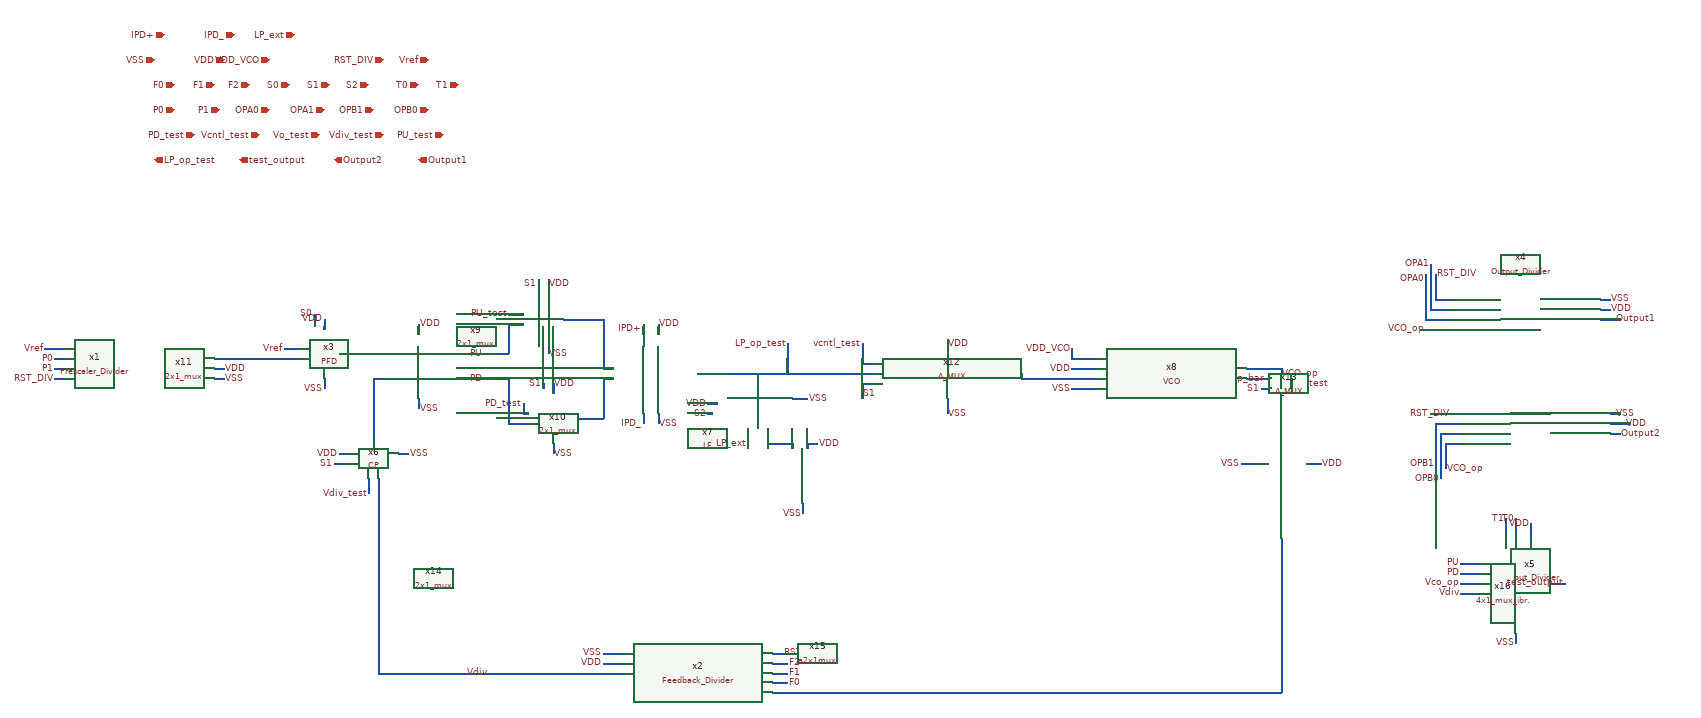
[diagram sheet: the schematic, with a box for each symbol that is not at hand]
v {xschem version=3.1.0 file_version=1.2
}
G {}
K {}
V {}
S {}
E {}
N 160 -760 180 -760 {
lab=P0}
N 160 -740 180 -740 {
lab=P1}
N 160 -720 180 -720 {
lab=RST_DIV}
N 480 -720 500 -720 {
lab=VSS}
N 480 -740 500 -740 {
lab=VDD}
N 890 -830 890 -810 {
lab=VDD}
N 890 -680 890 -660 {
lab=VSS}
N 800 -770 820 -770 {
lab=#net1}
N 800 -720 820 -720 {
lab=#net2}
N 960 -720 980 -720 {
lab=PD}
N 980 -770 1070 -770 {
lab=PU}
N 980 -720 1070 -720 {
lab=PD}
N 1010 -130 1300 -130 {
lab=Vdiv}
N 2200 -760 2240 -760 {
lab=VDD_VCO}
N 960 -770 980 -770 {
lab=PU}
N 2200 -780 2200 -760 {
lab=VDD_VCO}
N 1260 -170 1300 -170 {
lab=VSS}
N 1260 -150 1300 -150 {
lab=VDD}
N 1600 -150 1630 -150 {
lab=F2}
N 1600 -170 1630 -170 {
lab=RST_DIV}
N 2240 -760 2250 -760 {
lab=VDD_VCO}
N 1600 -110 1630 -110 {
lab=F0}
N 1600 -130 1630 -130 {
lab=F1}
N 2930 -880 2960 -880 {
lab=RST_DIV}
N 2930 -930 2930 -880 {
lab=RST_DIV}
N 2900 -820 2960 -820 {
lab=VCO_op}
N 2920 -860 2960 -860 {
lab=OPA1}
N 2920 -930 2920 -860 {
lab=OPA1}
N 2910 -840 2960 -840 {
lab=OPA0}
N 2910 -930 2910 -840 {
lab=OPA0}
N 3260 -880 3280 -880 {
lab=VSS}
N 3260 -860 3280 -860 {
lab=VDD}
N 3260 -840 3300 -840 {
lab=Output1}
N 2920 -950 2920 -930 {
lab=OPA1}
N 2950 -590 2980 -590 {
lab=VCO_op}
N 2950 -590 2950 -540 {
lab=VCO_op}
N 2920 -650 2980 -650 {
lab=RST_DIV}
N 2940 -610 2980 -610 {
lab=OPB0}
N 2940 -610 2940 -540 {
lab=OPB0}
N 2930 -630 2980 -630 {
lab=OPB1}
N 2930 -630 2930 -540 {
lab=OPB1}
N 3280 -650 3300 -650 {
lab=VSS}
N 3280 -610 3300 -610 {
lab=Output2}
N 3280 -630 3320 -630 {
lab=VDD}
N 2940 -540 2940 -520 {
lab=OPB0}
N 1370 -830 1370 -810 {
lab=VDD}
N 1370 -650 1370 -630 {
lab=VSS}
N 1260 -740 1280 -740 {
lab=#net3}
N 1260 -720 1280 -720 {
lab=#net4}
N 1340 -830 1340 -810 {
lab=IPD+}
N 1340 -650 1340 -630 {
lab=IPD_}
N 570 -760 600 -760 {
lab=#net5}
N 140 -780 170 -780 {
lab=Vref}
N 480 -760 550 -760 {
lab=#net5}
N 550 -760 570 -760 {
lab=#net5}
N 170 -780 180 -780 {
lab=Vref}
N 1070 -720 1070 -630 {
lab=PD}
N 1070 -630 1110 -630 {
lab=PD}
N 1100 -650 1110 -650 {
lab=PD_test}
N 1100 -670 1100 -650 {
lab=PD_test}
N 1070 -830 1070 -770 {
lab=PU}
N 1070 -830 1100 -830 {
lab=PU}
N 1150 -790 1150 -770 {
lab=VSS}
N 1140 -710 1140 -700 {
lab=S1}
N 1160 -710 1160 -690 {
lab=VDD}
N 1180 -840 1260 -840 {
lab=#net3}
N 1260 -840 1260 -770 {
lab=#net3}
N 1260 -720 1260 -640 {
lab=#net4}
N 1190 -640 1260 -640 {
lab=#net4}
N 1260 -770 1260 -740 {
lab=#net3}
N 1130 -920 1130 -900 {
lab=S1}
N 1150 -920 1150 -890 {
lab=VDD}
N 1070 -850 1100 -850 {
lab=PU_test}
N 1160 -590 1160 -570 {
lab=VSS}
N 700 -720 700 -700 {
lab=VSS}
N 700 -840 700 -820 {
lab=VDD}
N 680 -850 680 -830 {
lab=S0}
N 600 -760 650 -760 {
lab=#net5}
N 620 -780 650 -780 {
lab=Vref}
N 1950 -800 1950 -780 {
lab=VDD}
N 1950 -680 1950 -650 {
lab=VSS}
N 1780 -750 1800 -750 {
lab=vcntl_test}
N 1780 -790 1780 -750 {
lab=vcntl_test}
N 1780 -710 1800 -710 {
lab=S1}
N 1780 -710 1780 -680 {
lab=S1}
N 2640 -720 2640 -700 {
lab=Vo_test}
N 2620 -110 2620 -100 {
lab=#net6}
N 2540 -550 2570 -550 {
lab=VSS}
N 2670 -550 2700 -550 {
lab=VDD}
N 2580 -700 2600 -700 {
lab=S1}
N 2620 -100 2620 -90 {
lab=#net6}
N 2270 -90 2620 -90 {
lab=#net6}
N 1600 -90 2270 -90 {
lab=#net6}
N 2100 -720 2250 -720 {
lab=#net7}
N 2100 -730 2100 -720 {
lab=#net7}
N 2200 -740 2250 -740 {
lab=VDD}
N 2200 -700 2250 -700 {
lab=VSS}
N 2550 -740 2620 -740 {
lab=VCO_op}
N 2550 -720 2600 -720 {
lab=VCO_op_bar}
N 2620 -740 2620 -700 {
lab=VCO_op}
N 730 -770 790 -770 {
lab=#net1}
N 850 -570 870 -570 {
lab=VSS}
N 730 -570 750 -570 {
lab=VDD}
N 720 -550 740 -550 {
lab=S1}
N 810 -520 810 -470 {
lab=Vdiv}
N 790 -520 790 -490 {
lab=Vdiv_test}
N 800 -660 800 -600 {
lab=#net2}
N 810 -470 810 -420 {
lab=Vdiv}
N 800 -720 800 -660 {
lab=#net2}
N 790 -770 800 -770 {
lab=#net1}
N 1660 -470 1660 -450 {
lab=VSS}
N 1670 -590 1670 -580 {
lab=VDD}
N 1670 -590 1690 -590 {
lab=VDD}
N 1470 -670 1490 -670 {
lab=VDD}
N 1640 -680 1670 -680 {
lab=VSS}
N 1550 -620 1550 -590 {
lab=LP_ext}
N 1640 -590 1640 -580 {
lab=#net8}
N 1590 -590 1640 -590 {
lab=#net8}
N 1590 -620 1590 -590 {
lab=#net8}
N 1570 -730 1570 -720 {
lab=LP_op_test}
N 810 -130 1010 -130 {
lab=Vdiv}
N 810 -420 810 -300 {
lab=Vdiv}
N 2620 -230 2620 -110 {
lab=#net6}
N 810 -300 810 -130 {
lab=Vdiv}
N 2620 -400 2620 -240 {
lab=#net6}
N 2620 -240 2620 -230 {
lab=#net6}
N 1470 -650 1480 -650 {
lab=S2}
N 1450 -730 1800 -730 {
lab=LP_op_test}
N 2980 -350 3020 -350 {
lab=PU}
N 2980 -330 3020 -330 {
lab=PD}
N 2980 -310 3020 -310 {
lab=Vco_op}
N 2980 -290 3020 -290 {
lab=Vdiv}
N 1630 -790 1630 -730 {
lab=LP_op_test}
N 3120 -430 3120 -400 {
lab=VDD}
N 3090 -440 3090 -410 {
lab=T0}
N 3070 -440 3070 -410 {
lab=T1}
N 3090 -210 3090 -190 {
lab=VSS}
N 3160 -310 3190 -310 {
lab=test_output}
C {devices/ipin.sym} 710 -1310 0 0 {name=p45 lab=S1}
C {devices/ipin.sym} 630 -1310 0 0 {name=p46 lab=S0}
C {devices/ipin.sym} 890 -1310 0 0 {name=p47 lab=T0}
C {devices/ipin.sym} 970 -1310 0 0 {name=p48 lab=T1}
C {devices/iopin.sym} 500 -1360 0 0 {name=p58 lab=VDD}
C {devices/iopin.sym} 590 -1360 0 0 {name=p59 lab=VDD_VCO}
C {devices/ipin.sym} 910 -1360 0 0 {name=p60 lab=Vref}
C {devices/ipin.sym} 480 -1310 0 0 {name=p62 lab=F1}
C {devices/ipin.sym} 550 -1310 0 0 {name=p63 lab=F2}
C {devices/ipin.sym} 400 -1260 0 0 {name=p64 lab=P0}
C {devices/ipin.sym} 490 -1260 0 0 {name=p65 lab=P1}
C {devices/ipin.sym} 590 -1260 0 0 {name=p66 lab=OPA0}
C {devices/ipin.sym} 820 -1360 0 0 {name=p67 lab=RST_DIV}
C {devices/ipin.sym} 400 -1310 0 0 {name=p68 lab=F0}
C {devices/ipin.sym} 700 -1260 0 0 {name=p69 lab=OPA1}
C {devices/ipin.sym} 800 -1260 0 0 {name=p70 lab=OPB1}
C {devices/ipin.sym} 910 -1260 0 0 {name=p71 lab=OPB0}
C {devices/ipin.sym} 820 -1210 0 0 {name=p72 lab=Vdiv_test}
C {devices/ipin.sym} 940 -1210 0 0 {name=p73 lab=PU_test}
C {devices/ipin.sym} 440 -1210 0 0 {name=p74 lab=PD_test}
C {devices/ipin.sym} 570 -1210 0 0 {name=p75 lab=Vcntl_test}
C {devices/ipin.sym} 690 -1210 0 0 {name=p76 lab=Vo_test}
C {devices/opin.sym} 360 -1160 0 0 {name=p77 lab=LP_op_test}
C {devices/opin.sym} 530 -1160 0 0 {name=p78 lab=test_output}
C {devices/opin.sym} 720 -1160 0 0 {name=p79 lab=Output2}
C {devices/opin.sym} 890 -1160 0 0 {name=p80 lab=Output1}
C {devices/iopin.sym} 360 -1360 0 0 {name=p57 lab=VSS}
C {devices/lab_pin.sym} 160 -740 0 0 {name=p139 sig_type=std_logic lab=P1}
C {devices/lab_pin.sym} 160 -760 0 0 {name=p140 sig_type=std_logic lab=P0}
C {devices/lab_pin.sym} 140 -780 0 0 {name=p141 sig_type=std_logic lab=Vref
}
C {devices/lab_pin.sym} 500 -720 2 0 {name=p142 sig_type=std_logic lab=VSS}
C {devices/lab_pin.sym} 500 -740 2 0 {name=p143 sig_type=std_logic lab=VDD}
C {devices/lab_pin.sym} 160 -720 0 0 {name=p144 sig_type=std_logic lab=RST_DIV}
C {PFD.sym} 600 -560 0 0 {name=x3}
C {devices/lab_pin.sym} 890 -830 2 0 {name=p9 sig_type=std_logic lab=VDD}
C {devices/lab_wire.sym} 890 -660 2 0 {name=p10 sig_type=std_logic lab=VSS}
C {devices/lab_pin.sym} 1030 -130 1 0 {name=p28 sig_type=std_logic lab=Vdiv
}
C {devices/lab_pin.sym} 2200 -780 0 0 {name=p12 sig_type=std_logic lab=VDD_VCO}
C {devices/lab_pin.sym} 2590 -720 1 0 {name=p13 sig_type=std_logic lab=VCO_op_bar
}
C {devices/lab_pin.sym} 1260 -150 0 0 {name=p14 sig_type=std_logic lab=VDD}
C {devices/lab_wire.sym} 1260 -170 1 0 {name=p15 sig_type=std_logic lab=VSS}
C {devices/lab_pin.sym} 1630 -790 1 0 {name=p19 sig_type=std_logic lab=LP_op_test
}
C {devices/lab_pin.sym} 1020 -770 1 0 {name=p20 sig_type=std_logic lab=PU}
C {devices/lab_pin.sym} 1020 -720 1 0 {name=p21 sig_type=std_logic lab=PD}
C {Feedback_Divider.sym} 1450 -130 0 1 {name=x2}
C {devices/lab_pin.sym} 1630 -110 2 0 {name=p22 sig_type=std_logic lab=F0}
C {devices/lab_pin.sym} 1630 -130 2 0 {name=p23 sig_type=std_logic lab=F1}
C {devices/lab_pin.sym} 1630 -150 2 0 {name=p24 sig_type=std_logic lab=F2}
C {devices/lab_pin.sym} 3280 -860 2 0 {name=p32 sig_type=std_logic lab=VDD}
C {devices/lab_pin.sym} 3280 -880 2 0 {name=p33 sig_type=std_logic lab=VSS}
C {devices/lab_wire.sym} 2910 -920 0 0 {name=p82 sig_type=std_logic lab=OPA0}
C {devices/lab_wire.sym} 2920 -950 0 0 {name=p83 sig_type=std_logic lab=OPA1}
C {devices/lab_pin.sym} 2930 -930 2 0 {name=p34 sig_type=std_logic lab=RST_DIV}
C {devices/lab_pin.sym} 3290 -840 2 0 {name=p84 sig_type=std_logic lab=Output1}
C {devices/lab_pin.sym} 3310 -630 0 1 {name=p85 sig_type=std_logic lab=VDD}
C {devices/lab_pin.sym} 3290 -650 0 1 {name=p86 sig_type=std_logic lab=VSS}
C {devices/lab_wire.sym} 2930 -550 2 1 {name=p87 sig_type=std_logic lab=OPB1}
C {devices/lab_wire.sym} 2940 -520 2 1 {name=p88 sig_type=std_logic lab=OPB0}
C {devices/lab_pin.sym} 3300 -610 0 1 {name=p90 sig_type=std_logic lab=Output2}
C {Output_Divider.sym} 3130 -620 0 0 {name=x5}
C {devices/lab_pin.sym} 2960 -650 1 0 {name=p35 sig_type=std_logic lab=RST_DIV}
C {devices/lab_pin.sym} 2950 -540 2 0 {name=p37 sig_type=std_logic lab=VCO_op
}
C {devices/lab_pin.sym} 2910 -820 2 1 {name=p40 sig_type=std_logic lab=VCO_op
}
C {devices/lab_pin.sym} 1620 -170 2 0 {name=p39 sig_type=std_logic lab=RST_DIV}
C {devices/lab_wire.sym} 1370 -630 2 0 {name=p1 sig_type=std_logic lab=VSS}
C {devices/lab_pin.sym} 1370 -830 2 0 {name=p50 sig_type=std_logic lab=VDD}
C {CP.sym} 790 -530 0 0 {name=x6}
C {devices/lab_wire.sym} 1340 -820 0 0 {name=p52 sig_type=std_logic lab=IPD+}
C {devices/lab_wire.sym} 1340 -630 0 0 {name=p53 sig_type=std_logic lab=IPD_}
C {Output_Divider.sym} 3110 -850 0 0 {name=x4}
C {2x1_mux.sym} 900 -720 0 0 {name=x9}
C {2x1_mux.sym} 910 -520 0 0 {name=x10}
C {devices/lab_pin.sym} 1070 -850 0 0 {name=p2 sig_type=std_logic lab=PU_test
}
C {devices/lab_pin.sym} 1100 -670 1 0 {name=p3 sig_type=std_logic lab=PD_test
}
C {devices/lab_pin.sym} 1150 -910 2 0 {name=p4 sig_type=std_logic lab=VDD}
C {devices/lab_pin.sym} 1160 -710 2 0 {name=p5 sig_type=std_logic lab=VDD}
C {devices/lab_wire.sym} 1160 -570 2 0 {name=p6 sig_type=std_logic lab=VSS}
C {devices/lab_wire.sym} 1150 -770 2 0 {name=p7 sig_type=std_logic lab=VSS}
C {devices/lab_pin.sym} 1130 -910 1 0 {name=p106 sig_type=std_logic lab=S1}
C {devices/lab_pin.sym} 1140 -710 1 0 {name=p8 sig_type=std_logic lab=S1}
C {2x1_mux.sym} 450 -650 0 0 {name=x11}
C {devices/lab_wire.sym} 700 -700 3 0 {name=p11 sig_type=std_logic lab=VSS}
C {devices/lab_pin.sym} 700 -840 3 1 {name=p16 sig_type=std_logic lab=VDD}
C {devices/lab_pin.sym} 680 -850 1 0 {name=p17 sig_type=std_logic lab=S0}
C {devices/lab_pin.sym} 620 -780 1 0 {name=p18 sig_type=std_logic lab=Vref
}
C {A_MUX.sym} 1950 -730 0 0 {name=x12}
C {devices/lab_pin.sym} 1950 -790 2 0 {name=p25 sig_type=std_logic lab=VDD}
C {devices/lab_wire.sym} 1950 -650 2 0 {name=p26 sig_type=std_logic lab=VSS}
C {devices/lab_pin.sym} 1780 -690 2 0 {name=p27 sig_type=std_logic lab=S1}
C {devices/lab_pin.sym} 1780 -790 0 0 {name=p29 sig_type=std_logic lab=vcntl_test
}
C {devices/lab_pin.sym} 2620 -730 2 0 {name=p30 sig_type=std_logic lab=VCO_op
}
C {devices/lab_pin.sym} 2640 -710 2 0 {name=p31 sig_type=std_logic lab=Vo_test
}
C {A_MUX.sym} 2620 -550 1 0 {name=x13}
C {devices/lab_pin.sym} 2580 -700 0 0 {name=p36 sig_type=std_logic lab=S1}
C {devices/lab_wire.sym} 2540 -550 0 0 {name=p38 sig_type=std_logic lab=VSS}
C {devices/lab_pin.sym} 2700 -550 2 0 {name=p41 sig_type=std_logic lab=VDD}
C {devices/lab_pin.sym} 2200 -740 0 0 {name=p42 sig_type=std_logic lab=VDD}
C {devices/lab_wire.sym} 2200 -700 2 1 {name=p89 sig_type=std_logic lab=VSS}
C {2x1_mux.sym} 920 -320 3 0 {name=x14}
C {devices/lab_wire.sym} 870 -570 2 0 {name=p91 sig_type=std_logic lab=VSS}
C {devices/lab_pin.sym} 730 -570 2 1 {name=p92 sig_type=std_logic lab=VDD}
C {devices/lab_pin.sym} 720 -550 0 0 {name=p93 sig_type=std_logic lab=S1}
C {devices/lab_pin.sym} 790 -490 0 0 {name=p94 sig_type=std_logic lab=Vdiv_test

}
C {devices/lab_wire.sym} 1660 -450 2 1 {name=p43 sig_type=std_logic lab=VSS}
C {devices/lab_wire.sym} 1690 -590 0 1 {name=p98 sig_type=std_logic lab=VDD}
C {devices/lab_wire.sym} 1670 -680 2 0 {name=p99 sig_type=std_logic lab=VSS}
C {devices/lab_wire.sym} 1470 -670 2 1 {name=p100 sig_type=std_logic lab=VDD}
C {devices/lab_wire.sym} 1470 -650 1 1 {name=p44 sig_type=std_logic lab=S2}
C {LF.sym} 1800 -420 0 1 {name=x7}
C {a2x1mux.sym} 1730 -300 3 0 {name=x15}
C {4x1_mux_ibr..sym} 2740 -200 0 0 {name=x16}
C {devices/lab_pin.sym} 2980 -350 0 0 {name=p97 sig_type=std_logic lab=PU}
C {devices/lab_pin.sym} 2980 -330 0 0 {name=p54 sig_type=std_logic lab=PD}
C {devices/lab_pin.sym} 2980 -310 0 0 {name=p55 sig_type=std_logic lab=Vco_op
}
C {devices/lab_pin.sym} 2980 -290 0 0 {name=p105 sig_type=std_logic lab=Vdiv
}
C {devices/lab_pin.sym} 3070 -440 1 0 {name=p107 sig_type=std_logic lab=T1}
C {devices/lab_pin.sym} 3090 -440 1 0 {name=p108 sig_type=std_logic lab=T0}
C {devices/lab_pin.sym} 3120 -430 3 1 {name=p109 sig_type=std_logic lab=VDD}
C {devices/lab_wire.sym} 3090 -190 3 0 {name=p110 sig_type=std_logic lab=VSS}
C {devices/lab_pin.sym} 3190 -310 1 1 {name=p111 sig_type=std_logic lab=test_output}
C {devices/ipin.sym} 790 -1310 0 0 {name=p56 lab=S2}
C {Prescaler_Divider.sym} 330 -750 2 1 {name=x1}
C {devices/iopin.sym} 380 -1410 0 0 {name=p49 lab=IPD+}
C {devices/iopin.sym} 520 -1410 0 0 {name=p61 lab=IPD_}
C {devices/lab_pin.sym} 1550 -590 0 0 {name=p81 sig_type=std_logic lab=LP_ext}
C {devices/iopin.sym} 640 -1410 0 0 {name=p136 lab=LP_ext}
C {VCO.sym} 2400 -730 0 0 {name=x8}
